VERSION 5.6 ;
NAMESCASESENSITIVE ON ;
BUSBITCHARS "[]" ;
DIVIDERCHAR "/" ;

PROPERTYDEFINITIONS
END PROPERTYDEFINITIONS

UNITS
    DATABASE MICRONS 2000 ;
END UNITS
MANUFACTURINGGRID 0.005 ;

LAYER poly
    TYPE MASTERSLICE ;
END poly

LAYER active
    TYPE MASTERSLICE ;
END active

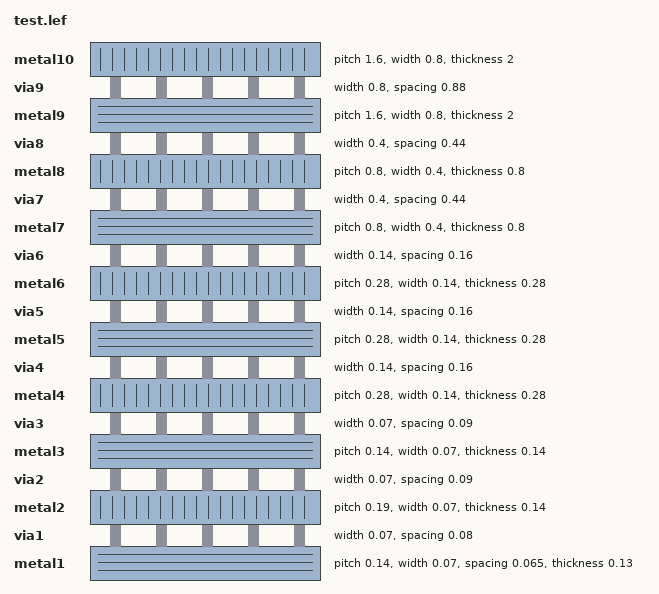
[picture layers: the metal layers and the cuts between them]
LAYER metal1
    TYPE ROUTING ;
    PITCH 0.14 ;
    WIDTH 0.07 ;
    THICKNESS 0.13 ;
    SPACING 0.065  ;
    DIRECTION HORIZONTAL ;
    RESISTANCE RPERSQ 0.38 ;
    CAPACITANCE CPERSQDIST 7.7161e-05 ;
    EDGECAPACITANCE 2.7365e-05 ;
END metal1

LAYER via1
    TYPE CUT ;
    WIDTH 0.07 ;
    SPACING 0.08  ;
    RESISTANCE 5 ;
END via1

LAYER metal2
    TYPE ROUTING ;
    PITCH 0.19 ;
    WIDTH 0.07 ;
    THICKNESS 0.14 ;
SPACINGTABLE
  PARALLELRUNLENGTH 0.000 0.300 0.900 1.800 2.700 4.000
  WIDTH 0.000	 0.070 0.070 0.070 0.070 0.070 0.070
  WIDTH 0.090	 0.070 0.090 0.090 0.090 0.090 0.090
  WIDTH 0.270	 0.070 0.090 0.270 0.270 0.270 0.270
  WIDTH 0.500	 0.070 0.090 0.270 0.500 0.500 0.500
  WIDTH 0.900	 0.070 0.090 0.270 0.500 0.900 0.900
  WIDTH 1.500	 0.070 0.090 0.270 0.500 0.900 1.500 ;
    DIRECTION VERTICAL ;
    RESISTANCE RPERSQ 0.25 ;
    CAPACITANCE CPERSQDIST 4.0896e-05 ;
    EDGECAPACITANCE 2.5157e-05 ;
END metal2

LAYER via2
    TYPE CUT ;
    WIDTH 0.07 ;
    SPACING 0.09  ;
    RESISTANCE 5 ;
END via2

LAYER metal3
    TYPE ROUTING ;
    PITCH 0.14 ;
    WIDTH 0.07 ;
    THICKNESS 0.14 ;
SPACINGTABLE
  PARALLELRUNLENGTH 0.000 0.300 0.900 1.800 2.700 4.000
  WIDTH 0.000	 0.070 0.070 0.070 0.070 0.070 0.070
  WIDTH 0.090	 0.070 0.090 0.090 0.090 0.090 0.090
  WIDTH 0.270	 0.070 0.090 0.270 0.270 0.270 0.270
  WIDTH 0.500	 0.070 0.090 0.270 0.500 0.500 0.500
  WIDTH 0.900	 0.070 0.090 0.270 0.500 0.900 0.900
  WIDTH 1.500	 0.070 0.090 0.270 0.500 0.900 1.500 ;
    DIRECTION HORIZONTAL ;
    RESISTANCE RPERSQ 0.25 ;
    CAPACITANCE CPERSQDIST 2.7745e-05 ;
    EDGECAPACITANCE 2.5157e-05 ;
END metal3

LAYER via3
    TYPE CUT ;
    WIDTH 0.07 ;
    SPACING 0.09  ;
    RESISTANCE 5 ;
END via3

LAYER metal4
    TYPE ROUTING ;
    PITCH 0.28 ;
    WIDTH 0.14 ;
    THICKNESS 0.28 ;
SPACINGTABLE
  PARALLELRUNLENGTH 0.000 0.900 1.800 2.700 4.000
  WIDTH 0.000	 0.140 0.140 0.140 0.140 0.140
  WIDTH 0.270	 0.140 0.270 0.270 0.270 0.270
  WIDTH 0.500	 0.140 0.270 0.500 0.500 0.500
  WIDTH 0.900	 0.140 0.270 0.500 0.900 0.900
  WIDTH 1.500	 0.140 0.270 0.500 0.900 1.500 ;
    DIRECTION VERTICAL ;
    RESISTANCE RPERSQ 0.21 ;
    CAPACITANCE CPERSQDIST 2.0743e-05 ;
    EDGECAPACITANCE 3.0908e-05 ;
END metal4

LAYER via4
    TYPE CUT ;
    WIDTH 0.14 ;
    SPACING 0.16  ;
    RESISTANCE 3 ;
END via4

LAYER metal5
    TYPE ROUTING ;
    PITCH 0.28 ;
    WIDTH 0.14 ;
    THICKNESS 0.28 ;
SPACINGTABLE
  PARALLELRUNLENGTH 0.000 0.900 1.800 2.700 4.000
  WIDTH 0.000	 0.140 0.140 0.140 0.140 0.140
  WIDTH 0.270	 0.140 0.270 0.270 0.270 0.270
  WIDTH 0.500	 0.140 0.270 0.500 0.500 0.500
  WIDTH 0.900	 0.140 0.270 0.500 0.900 0.900
  WIDTH 1.500	 0.140 0.270 0.500 0.900 1.500 ;
    DIRECTION HORIZONTAL ;
    RESISTANCE RPERSQ 0.21 ;
    CAPACITANCE CPERSQDIST 1.3527e-05 ;
    EDGECAPACITANCE 2.3863e-06 ;
END metal5

LAYER via5
    TYPE CUT ;
    WIDTH 0.14 ;
    SPACING 0.16  ;
    RESISTANCE 3 ;
END via5

LAYER metal6
    TYPE ROUTING ;
    PITCH 0.28 ;
    WIDTH 0.14 ;
    THICKNESS 0.28 ;
SPACINGTABLE
  PARALLELRUNLENGTH 0.000 0.900 1.800 2.700 4.000
  WIDTH 0.000	 0.140 0.140 0.140 0.140 0.140
  WIDTH 0.270	 0.140 0.270 0.270 0.270 0.270
  WIDTH 0.500	 0.140 0.270 0.500 0.500 0.500
  WIDTH 0.900	 0.140 0.270 0.500 0.900 0.900
  WIDTH 1.500	 0.140 0.270 0.500 0.900 1.500 ;
    DIRECTION VERTICAL ;
    RESISTANCE RPERSQ 0.21 ;
    CAPACITANCE CPERSQDIST 1.0036e-05 ;
    EDGECAPACITANCE 2.3863e-05 ;
END metal6

LAYER via6
    TYPE CUT ;
    WIDTH 0.14 ;
    SPACING 0.16  ;
    RESISTANCE 3 ;
END via6

LAYER metal7
    TYPE ROUTING ;
    PITCH 0.8 ;
    WIDTH 0.4 ;
    THICKNESS 0.8 ;
SPACINGTABLE
  PARALLELRUNLENGTH 0.000 1.800 2.700 4.000
  WIDTH 0.000	 0.400 0.400 0.400 0.400
  WIDTH 0.500	 0.400 0.500 0.500 0.500
  WIDTH 0.900	 0.400 0.500 0.900 0.900
  WIDTH 1.500	 0.400 0.500 0.900 1.500 ;
    DIRECTION HORIZONTAL ;
    RESISTANCE RPERSQ 0.075 ;
    CAPACITANCE CPERSQDIST 7.9771e-06 ;
    EDGECAPACITANCE 3.2577e-05 ;
END metal7

LAYER via7
    TYPE CUT ;
    WIDTH 0.4 ;
    SPACING 0.44  ;
    RESISTANCE 1 ;
END via7

LAYER metal8
    TYPE ROUTING ;
    PITCH 0.8 ;
    WIDTH 0.4 ;
    THICKNESS 0.8 ;
SPACINGTABLE
  PARALLELRUNLENGTH 0.000 1.800 2.700 4.000
  WIDTH 0.000	 0.400 0.400 0.400 0.400
  WIDTH 0.500	 0.400 0.500 0.500 0.500
  WIDTH 0.900	 0.400 0.500 0.900 0.900
  WIDTH 1.500	 0.400 0.500 0.900 1.500 ;
    DIRECTION VERTICAL ;
    RESISTANCE RPERSQ 0.075 ;
    CAPACITANCE CPERSQDIST 5.0391e-06 ;
    EDGECAPACITANCE 2.3932e-05 ;
END metal8

LAYER via8
    TYPE CUT ;
    WIDTH 0.4 ;
    SPACING 0.44  ;
    RESISTANCE 1 ;
END via8

LAYER metal9
    TYPE ROUTING ;
    PITCH 1.6 ;
    WIDTH 0.8 ;
    THICKNESS 2 ;
SPACINGTABLE
  PARALLELRUNLENGTH 0.000 2.700 4.000
  WIDTH 0.000	 0.800 0.800 0.800
  WIDTH 0.900	 0.800 0.900 0.900
  WIDTH 1.500	 0.800 0.900 1.500 ;
    DIRECTION HORIZONTAL ;
    RESISTANCE RPERSQ 0.03 ;
    CAPACITANCE CPERSQDIST 3.6827e-06 ;
    EDGECAPACITANCE 3.0803e-05 ;
END metal9

LAYER via9
    TYPE CUT ;
    WIDTH 0.8 ;
    SPACING 0.88  ;
    RESISTANCE 0.5 ;
END via9

LAYER metal10
    TYPE ROUTING ;
    PITCH 1.6 ;
    WIDTH 0.8 ;
    THICKNESS 2 ;
SPACINGTABLE
  PARALLELRUNLENGTH 0.000 2.700 4.000
  WIDTH 0.000	 0.800 0.800 0.800
  WIDTH 0.900	 0.800 0.900 0.900
  WIDTH 1.500	 0.800 0.900 1.500 ;
    DIRECTION VERTICAL ;
    RESISTANCE RPERSQ 0.03 ;
    CAPACITANCE CPERSQDIST 2.2124e-06 ;
    EDGECAPACITANCE 2.3667e-05 ;
END metal10

LAYER OVERLAP
    TYPE OVERLAP ;
END OVERLAP

VIA via1_4 DEFAULT
    LAYER via1 ;
      RECT  -0.035 -0.035 0.035 0.035 ;
    LAYER metal1 ;
      RECT  -0.035 -0.07 0.035 0.07 ;
    LAYER metal2 ;
      RECT  -0.035 -0.07 0.035 0.07 ;
END via1_4

VIA via1_0 DEFAULT
    LAYER via1 ;
      RECT  -0.035 -0.035 0.035 0.035 ;
    LAYER metal1 ;
      RECT  -0.07 -0.07 0.07 0.07 ;
    LAYER metal2 ;
      RECT  -0.07 -0.07 0.07 0.07 ;
END via1_0

VIA via1_1 DEFAULT
    LAYER via1 ;
      RECT  -0.035 -0.035 0.035 0.035 ;
    LAYER metal1 ;
      RECT  -0.07 -0.07 0.07 0.07 ;
    LAYER metal2 ;
      RECT  -0.035 -0.07 0.035 0.07 ;
END via1_1

VIA via1_2 DEFAULT
    LAYER via1 ;
      RECT  -0.035 -0.035 0.035 0.035 ;
    LAYER metal1 ;
      RECT  -0.07 -0.07 0.07 0.07 ;
    LAYER metal2 ;
      RECT  -0.07 -0.035 0.07 0.035 ;
END via1_2

VIA via1_3 DEFAULT
    LAYER via1 ;
      RECT  -0.035 -0.035 0.035 0.035 ;
    LAYER metal1 ;
      RECT  -0.035 -0.07 0.035 0.07 ;
    LAYER metal2 ;
      RECT  -0.07 -0.07 0.07 0.07 ;
END via1_3

VIA via1_5 DEFAULT
    LAYER via1 ;
      RECT  -0.035 -0.035 0.035 0.035 ;
    LAYER metal1 ;
      RECT  -0.035 -0.07 0.035 0.07 ;
    LAYER metal2 ;
      RECT  -0.07 -0.035 0.07 0.035 ;
END via1_5

VIA via1_6 DEFAULT
    LAYER via1 ;
      RECT  -0.035 -0.035 0.035 0.035 ;
    LAYER metal1 ;
      RECT  -0.07 -0.035 0.07 0.035 ;
    LAYER metal2 ;
      RECT  -0.07 -0.07 0.07 0.07 ;
END via1_6

VIA via1_7 DEFAULT
    LAYER via1 ;
      RECT  -0.035 -0.035 0.035 0.035 ;
    LAYER metal1 ;
      RECT  -0.07 -0.035 0.07 0.035 ;
    LAYER metal2 ;
      RECT  -0.035 -0.07 0.035 0.07 ;
END via1_7

VIA via1_8 DEFAULT
    LAYER via1 ;
      RECT  -0.035 -0.035 0.035 0.035 ;
    LAYER metal1 ;
      RECT  -0.07 -0.035 0.07 0.035 ;
    LAYER metal2 ;
      RECT  -0.07 -0.035 0.07 0.035 ;
END via1_8

VIA via2_8 DEFAULT
    LAYER via2 ;
      RECT  -0.035 -0.035 0.035 0.035 ;
    LAYER metal2 ;
      RECT  -0.07 -0.035 0.07 0.035 ;
    LAYER metal3 ;
      RECT  -0.07 -0.035 0.07 0.035 ;
END via2_8

VIA via2_4 DEFAULT
    LAYER via2 ;
      RECT  -0.035 -0.035 0.035 0.035 ;
    LAYER metal2 ;
      RECT  -0.035 -0.07 0.035 0.07 ;
    LAYER metal3 ;
      RECT  -0.035 -0.07 0.035 0.07 ;
END via2_4

VIA via2_5 DEFAULT
    LAYER via2 ;
      RECT  -0.035 -0.035 0.035 0.035 ;
    LAYER metal2 ;
      RECT  -0.035 -0.07 0.035 0.07 ;
    LAYER metal3 ;
      RECT  -0.07 -0.035 0.07 0.035 ;
END via2_5

VIA via2_7 DEFAULT
    LAYER via2 ;
      RECT  -0.035 -0.035 0.035 0.035 ;
    LAYER metal2 ;
      RECT  -0.07 -0.035 0.07 0.035 ;
    LAYER metal3 ;
      RECT  -0.035 -0.07 0.035 0.07 ;
END via2_7

VIA via2_6 DEFAULT
    LAYER via2 ;
      RECT  -0.035 -0.035 0.035 0.035 ;
    LAYER metal2 ;
      RECT  -0.07 -0.035 0.07 0.035 ;
    LAYER metal3 ;
      RECT  -0.07 -0.07 0.07 0.07 ;
END via2_6

VIA via2_0 DEFAULT
    LAYER via2 ;
      RECT  -0.035 -0.035 0.035 0.035 ;
    LAYER metal2 ;
      RECT  -0.07 -0.07 0.07 0.07 ;
    LAYER metal3 ;
      RECT  -0.07 -0.07 0.07 0.07 ;
END via2_0

VIA via2_1 DEFAULT
    LAYER via2 ;
      RECT  -0.035 -0.035 0.035 0.035 ;
    LAYER metal2 ;
      RECT  -0.07 -0.07 0.07 0.07 ;
    LAYER metal3 ;
      RECT  -0.035 -0.07 0.035 0.07 ;
END via2_1

VIA via2_2 DEFAULT
    LAYER via2 ;
      RECT  -0.035 -0.035 0.035 0.035 ;
    LAYER metal2 ;
      RECT  -0.07 -0.07 0.07 0.07 ;
    LAYER metal3 ;
      RECT  -0.07 -0.035 0.07 0.035 ;
END via2_2

VIA via2_3 DEFAULT
    LAYER via2 ;
      RECT  -0.035 -0.035 0.035 0.035 ;
    LAYER metal2 ;
      RECT  -0.035 -0.07 0.035 0.07 ;
    LAYER metal3 ;
      RECT  -0.07 -0.07 0.07 0.07 ;
END via2_3

VIA via3_2 DEFAULT
    LAYER via3 ;
      RECT  -0.035 -0.035 0.035 0.035 ;
    LAYER metal3 ;
      RECT  -0.07 -0.035 0.07 0.035 ;
    LAYER metal4 ;
      RECT  -0.07 -0.07 0.07 0.07 ;
END via3_2

VIA via3_0 DEFAULT
    LAYER via3 ;
      RECT  -0.035 -0.035 0.035 0.035 ;
    LAYER metal3 ;
      RECT  -0.07 -0.07 0.07 0.07 ;
    LAYER metal4 ;
      RECT  -0.07 -0.07 0.07 0.07 ;
END via3_0

VIA via3_1 DEFAULT
    LAYER via3 ;
      RECT  -0.035 -0.035 0.035 0.035 ;
    LAYER metal3 ;
      RECT  -0.035 -0.07 0.035 0.07 ;
    LAYER metal4 ;
      RECT  -0.07 -0.07 0.07 0.07 ;
END via3_1

VIA via4_0 DEFAULT
    LAYER via4 ;
      RECT  -0.07 -0.07 0.07 0.07 ;
    LAYER metal4 ;
      RECT  -0.07 -0.07 0.07 0.07 ;
    LAYER metal5 ;
      RECT  -0.07 -0.07 0.07 0.07 ;
END via4_0

VIA via5_0 DEFAULT
    LAYER via5 ;
      RECT  -0.07 -0.07 0.07 0.07 ;
    LAYER metal5 ;
      RECT  -0.07 -0.07 0.07 0.07 ;
    LAYER metal6 ;
      RECT  -0.07 -0.07 0.07 0.07 ;
END via5_0

VIA via6_0 DEFAULT
    LAYER via6 ;
      RECT  -0.07 -0.07 0.07 0.07 ;
    LAYER metal6 ;
      RECT  -0.07 -0.07 0.07 0.07 ;
    LAYER metal7 ;
      RECT  -0.2 -0.2 0.2 0.2 ;
END via6_0

VIA via7_0 DEFAULT
    LAYER via7 ;
      RECT  -0.2 -0.2 0.2 0.2 ;
    LAYER metal7 ;
      RECT  -0.2 -0.2 0.2 0.2 ;
    LAYER metal8 ;
      RECT  -0.2 -0.2 0.2 0.2 ;
END via7_0

VIA via8_0 DEFAULT
    LAYER via8 ;
      RECT  -0.2 -0.2 0.2 0.2 ;
    LAYER metal8 ;
      RECT  -0.2 -0.2 0.2 0.2 ;
    LAYER metal9 ;
      RECT  -0.4 -0.4 0.4 0.4 ;
END via8_0

VIA via9_0 DEFAULT
    LAYER via9 ;
      RECT  -0.4 -0.4 0.4 0.4 ;
    LAYER metal9 ;
      RECT  -0.4 -0.4 0.4 0.4 ;
    LAYER metal10 ;
      RECT  -0.4 -0.4 0.4 0.4 ;
END via9_0

VIARULE Via1Array-0 GENERATE 
    LAYER metal1 ;
      ENCLOSURE 0.035 0.035 ;
    LAYER metal2 ;
      ENCLOSURE 0.035 0.035 ;
    LAYER via1 ;
      RECT  -0.035 -0.035  0.035 0.035  ;
      SPACING 0.15 BY 0.15 ;
END Via1Array-0

VIARULE Via1Array-1 GENERATE 
    LAYER metal1 ;
      ENCLOSURE 0 0.035 ;
    LAYER metal2 ;
      ENCLOSURE 0 0.035 ;
    LAYER via1 ;
      RECT  -0.035 -0.035  0.035 0.035  ;
      SPACING 0.15 BY 0.15 ;
END Via1Array-1

VIARULE Via1Array-2 GENERATE 
    LAYER metal1 ;
      ENCLOSURE 0.035 0 ;
    LAYER metal2 ;
      ENCLOSURE 0.035 0 ;
    LAYER via1 ;
      RECT  -0.035 -0.035  0.035 0.035  ;
      SPACING 0.15 BY 0.15 ;
END Via1Array-2

VIARULE Via1Array-3 GENERATE 
    LAYER metal1 ;
      ENCLOSURE 0 0.035 ;
    LAYER metal2 ;
      ENCLOSURE 0.035 0 ;
    LAYER via1 ;
      RECT  -0.035 -0.035  0.035 0.035  ;
      SPACING 0.15 BY 0.15 ;
END Via1Array-3

VIARULE Via1Array-4 GENERATE 
    LAYER metal1 ;
      ENCLOSURE 0.035 0 ;
    LAYER metal2 ;
      ENCLOSURE 0 0.035 ;
    LAYER via1 ;
      RECT  -0.035 -0.035  0.035 0.035  ;
      SPACING 0.15 BY 0.15 ;
END Via1Array-4

VIARULE Via2Array-0 GENERATE 
    LAYER metal2 ;
      ENCLOSURE 0.035 0.035 ;
    LAYER metal3 ;
      ENCLOSURE 0.035 0.035 ;
    LAYER via2 ;
      RECT  -0.035 -0.035  0.035 0.035  ;
      SPACING 0.16 BY 0.16 ;
END Via2Array-0

VIARULE Via2Array-1 GENERATE 
    LAYER metal2 ;
      ENCLOSURE 0 0.035 ;
    LAYER metal3 ;
      ENCLOSURE 0 0.035 ;
    LAYER via2 ;
      RECT  -0.035 -0.035  0.035 0.035  ;
      SPACING 0.16 BY 0.16 ;
END Via2Array-1

VIARULE Via2Array-2 GENERATE 
    LAYER metal2 ;
      ENCLOSURE 0.035 0 ;
    LAYER metal3 ;
      ENCLOSURE 0.035 0 ;
    LAYER via2 ;
      RECT  -0.035 -0.035  0.035 0.035  ;
      SPACING 0.16 BY 0.16 ;
END Via2Array-2

VIARULE Via2Array-3 GENERATE 
    LAYER metal2 ;
      ENCLOSURE 0 0.035 ;
    LAYER metal3 ;
      ENCLOSURE 0.035 0 ;
    LAYER via2 ;
      RECT  -0.035 -0.035  0.035 0.035  ;
      SPACING 0.16 BY 0.16 ;
END Via2Array-3

VIARULE Via2Array-4 GENERATE 
    LAYER metal2 ;
      ENCLOSURE 0.035 0 ;
    LAYER metal3 ;
      ENCLOSURE 0 0.035 ;
    LAYER via2 ;
      RECT  -0.035 -0.035  0.035 0.035  ;
      SPACING 0.16 BY 0.16 ;
END Via2Array-4

VIARULE Via3Array-0 GENERATE 
    LAYER metal3 ;
      ENCLOSURE 0.035 0.035 ;
    LAYER metal4 ;
      ENCLOSURE 0.035 0.035 ;
    LAYER via3 ;
      RECT  -0.035 -0.035  0.035 0.035  ;
      SPACING 0.16 BY 0.16 ;
END Via3Array-0

VIARULE Via3Array-1 GENERATE 
    LAYER metal3 ;
      ENCLOSURE 0 0.035 ;
    LAYER metal4 ;
      ENCLOSURE 0.035 0.035 ;
    LAYER via3 ;
      RECT  -0.035 -0.035  0.035 0.035  ;
      SPACING 0.16 BY 0.16 ;
END Via3Array-1

VIARULE Via3Array-2 GENERATE 
    LAYER metal3 ;
      ENCLOSURE 0.035 0 ;
    LAYER metal4 ;
      ENCLOSURE 0.035 0.035 ;
    LAYER via3 ;
      RECT  -0.035 -0.035  0.035 0.035  ;
      SPACING 0.16 BY 0.16 ;
END Via3Array-2

VIARULE Via4Array-0 GENERATE 
    LAYER metal4 ;
      ENCLOSURE 0 0 ;
    LAYER metal5 ;
      ENCLOSURE 0 0 ;
    LAYER via4 ;
      RECT  -0.07 -0.07  0.07 0.07  ;
      SPACING 0.3 BY 0.3 ;
END Via4Array-0

VIARULE Via5Array-0 GENERATE 
    LAYER metal5 ;
      ENCLOSURE 0 0 ;
    LAYER metal6 ;
      ENCLOSURE 0 0 ;
    LAYER via5 ;
      RECT  -0.07 -0.07  0.07 0.07  ;
      SPACING 0.3 BY 0.3 ;
END Via5Array-0

VIARULE Via6Array-0 GENERATE 
    LAYER metal6 ;
      ENCLOSURE 0 0 ;
    LAYER metal7 ;
      ENCLOSURE 0.13 0.13 ;
    LAYER via6 ;
      RECT  -0.07 -0.07  0.07 0.07  ;
      SPACING 0.3 BY 0.3 ;
END Via6Array-0

VIARULE Via7Array-0 GENERATE 
    LAYER metal7 ;
      ENCLOSURE 0 0 ;
    LAYER metal8 ;
      ENCLOSURE 0 0 ;
    LAYER via7 ;
      RECT  -0.2 -0.2  0.2 0.2  ;
      SPACING 0.84 BY 0.84 ;
END Via7Array-0

VIARULE Via8Array-0 GENERATE 
    LAYER metal8 ;
      ENCLOSURE 0 0 ;
    LAYER metal9 ;
      ENCLOSURE 0.2 0.2 ;
    LAYER via8 ;
      RECT  -0.2 -0.2  0.2 0.2  ;
      SPACING 0.84 BY 0.84 ;
END Via8Array-0

VIARULE Via9Array-0 GENERATE 
    LAYER metal10 ;
      ENCLOSURE 0 0 ;
    LAYER metal9 ;
      ENCLOSURE 0 0 ;
    LAYER via9 ;
      RECT  -0.4 -0.4  0.4 0.4  ;
      SPACING 1.68 BY 1.68 ;
END Via9Array-0

SPACING
  SAMENET metal1 metal1 0.065 ;
  SAMENET metal2 metal2 0.07 ;
  SAMENET metal3 metal3 0.07 ;
  SAMENET metal4 metal4 0.14 ;
  SAMENET metal5 metal5 0.14 ;
  SAMENET metal6 metal6 0.14 ;
  SAMENET metal7 metal7 0.4 ;
  SAMENET metal8 metal8 0.4 ;
  SAMENET metal9 metal9 0.8 ;
  SAMENET metal10 metal10 0.8 ;
  SAMENET via1 via1 0.08 ;
  SAMENET via2 via2 0.09 ;
  SAMENET via3 via3 0.09 ;
  SAMENET via4 via4 0.16 ;
  SAMENET via5 via5 0.16 ;
  SAMENET via6 via6 0.16 ;
  SAMENET via7 via7 0.44 ;
  SAMENET via8 via8 0.44 ;
  SAMENET via9 via9 0.88 ;
  SAMENET via1 via2 0 STACK ;
  SAMENET via2 via3 0 STACK ;
  SAMENET via3 via4 0 STACK ;
  SAMENET via4 via5 0 STACK ;
  SAMENET via5 via6 0 STACK ;
  SAMENET via6 via7 0 STACK ;
  SAMENET via7 via8 0 STACK ;
  SAMENET via8 via9 0 STACK ;

END SPACING
SITE FreePDK45_38x28_10R_NP_162NW_34O
    CLASS CORE ;
    SYMMETRY Y ;
    SIZE 0.19 BY 1.4 ;
END FreePDK45_38x28_10R_NP_162NW_34O
END LIBRARY
